VERSION 5.7 ;
  NOWIREEXTENSIONATPIN ON ;
  DIVIDERCHAR "/" ;
  BUSBITCHARS "[]" ;
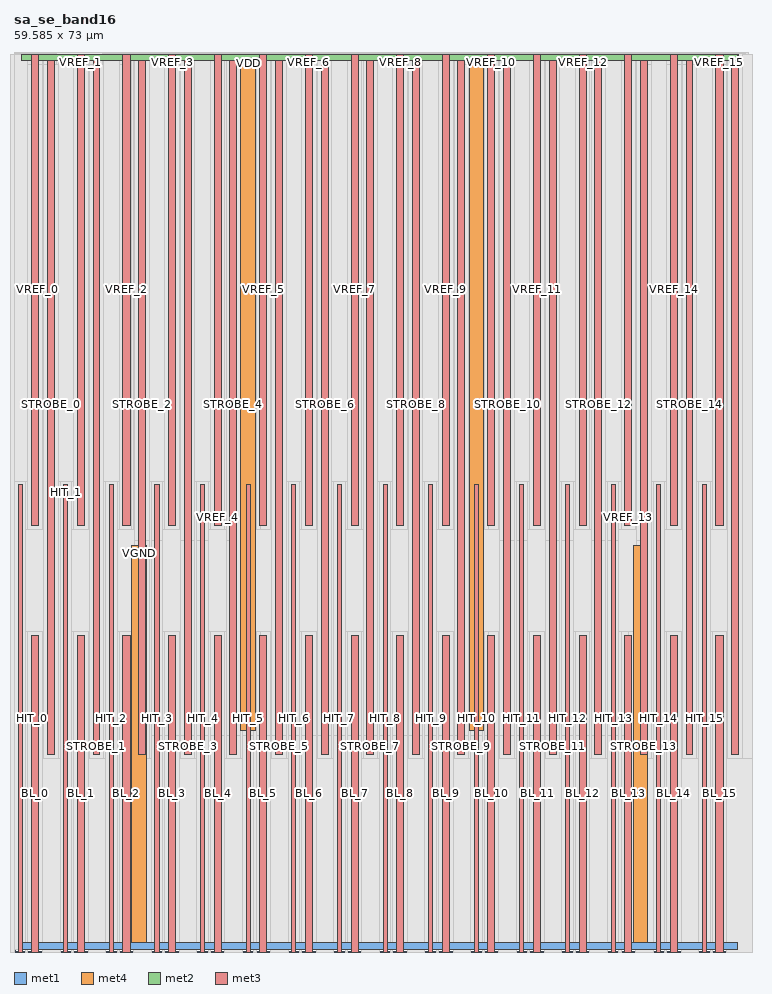
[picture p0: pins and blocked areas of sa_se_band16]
MACRO sa_se_band16
  CLASS BLOCK ;
  FOREIGN sa_se_band16 ;
  ORIGIN 0.300 0.000 ;
  SIZE 59.585 BY 73.000 ;
  PIN VGND
    USE GROUND ;
    PORT
      LAYER met1 ;
        RECT 0.300 0.200 58.360 0.800 ;
    END
    PORT
      LAYER met4 ;
        RECT 9.235 0.200 10.415 33.000 ;
    END
    PORT
      LAYER met4 ;
        RECT 49.935 0.200 51.115 33.000 ;
    END
  END VGND
  PIN VDD
    USE POWER ;
    PORT
      LAYER met2 ;
        RECT 0.300 72.300 58.360 72.800 ;
    END
    PORT
      LAYER met4 ;
        RECT 18.110 18.000 19.290 72.750 ;
    END
    PORT
      LAYER met4 ;
        RECT 36.610 18.000 37.790 72.750 ;
    END
  END VDD
  PIN HIT_0
    USE SIGNAL ;
    PORT
      LAYER met3 ;
        RECT 0.035 0.000 0.365 37.900 ;
    END
  END HIT_0
  PIN BL_0
    USE SIGNAL ;
    PORT
      LAYER met3 ;
        RECT 1.135 0.000 1.710 25.700 ;
    END
  END BL_0
  PIN VREF_0
    USE SIGNAL ;
    PORT
      LAYER met3 ;
        RECT 1.135 34.600 1.710 72.800 ;
    END
  END VREF_0
  PIN STROBE_0
    USE SIGNAL ;
    PORT
      LAYER met3 ;
        RECT 2.410 16.000 2.970 72.800 ;
    END
  END STROBE_0
  PIN HIT_1
    USE SIGNAL ;
    PORT
      LAYER met3 ;
        RECT 3.735 0.000 4.065 37.900 ;
    END
  END HIT_1
  PIN BL_1
    USE SIGNAL ;
    PORT
      LAYER met3 ;
        RECT 4.835 0.000 5.410 25.700 ;
    END
  END BL_1
  PIN VREF_1
    USE SIGNAL ;
    PORT
      LAYER met3 ;
        RECT 4.835 34.600 5.410 72.800 ;
    END
  END VREF_1
  PIN STROBE_1
    USE SIGNAL ;
    PORT
      LAYER met3 ;
        RECT 6.110 16.000 6.670 72.800 ;
    END
  END STROBE_1
  PIN HIT_2
    USE SIGNAL ;
    PORT
      LAYER met3 ;
        RECT 7.435 0.000 7.765 37.900 ;
    END
  END HIT_2
  PIN BL_2
    USE SIGNAL ;
    PORT
      LAYER met3 ;
        RECT 8.535 0.000 9.110 25.700 ;
    END
  END BL_2
  PIN VREF_2
    USE SIGNAL ;
    PORT
      LAYER met3 ;
        RECT 8.535 34.600 9.110 72.800 ;
    END
  END VREF_2
  PIN STROBE_2
    USE SIGNAL ;
    PORT
      LAYER met3 ;
        RECT 9.810 16.000 10.370 72.800 ;
    END
  END STROBE_2
  PIN HIT_3
    USE SIGNAL ;
    PORT
      LAYER met3 ;
        RECT 11.135 0.000 11.465 37.900 ;
    END
  END HIT_3
  PIN BL_3
    USE SIGNAL ;
    PORT
      LAYER met3 ;
        RECT 12.235 0.000 12.810 25.700 ;
    END
  END BL_3
  PIN VREF_3
    USE SIGNAL ;
    PORT
      LAYER met3 ;
        RECT 12.235 34.600 12.810 72.800 ;
    END
  END VREF_3
  PIN STROBE_3
    USE SIGNAL ;
    PORT
      LAYER met3 ;
        RECT 13.510 16.000 14.070 72.800 ;
    END
  END STROBE_3
  PIN HIT_4
    USE SIGNAL ;
    PORT
      LAYER met3 ;
        RECT 14.835 0.000 15.165 37.900 ;
    END
  END HIT_4
  PIN BL_4
    USE SIGNAL ;
    PORT
      LAYER met3 ;
        RECT 15.935 0.000 16.510 25.700 ;
    END
  END BL_4
  PIN VREF_4
    USE SIGNAL ;
    PORT
      LAYER met3 ;
        RECT 15.935 34.600 16.510 72.800 ;
    END
  END VREF_4
  PIN STROBE_4
    USE SIGNAL ;
    PORT
      LAYER met3 ;
        RECT 17.210 16.000 17.770 72.800 ;
    END
  END STROBE_4
  PIN HIT_5
    USE SIGNAL ;
    PORT
      LAYER met3 ;
        RECT 18.535 0.000 18.865 37.900 ;
    END
  END HIT_5
  PIN BL_5
    USE SIGNAL ;
    PORT
      LAYER met3 ;
        RECT 19.635 0.000 20.210 25.700 ;
    END
  END BL_5
  PIN VREF_5
    USE SIGNAL ;
    PORT
      LAYER met3 ;
        RECT 19.635 34.600 20.210 72.800 ;
    END
  END VREF_5
  PIN STROBE_5
    USE SIGNAL ;
    PORT
      LAYER met3 ;
        RECT 20.910 16.000 21.470 72.800 ;
    END
  END STROBE_5
  PIN HIT_6
    USE SIGNAL ;
    PORT
      LAYER met3 ;
        RECT 22.235 0.000 22.565 37.900 ;
    END
  END HIT_6
  PIN BL_6
    USE SIGNAL ;
    PORT
      LAYER met3 ;
        RECT 23.335 0.000 23.910 25.700 ;
    END
  END BL_6
  PIN VREF_6
    USE SIGNAL ;
    PORT
      LAYER met3 ;
        RECT 23.335 34.600 23.910 72.800 ;
    END
  END VREF_6
  PIN STROBE_6
    USE SIGNAL ;
    PORT
      LAYER met3 ;
        RECT 24.610 16.000 25.170 72.800 ;
    END
  END STROBE_6
  PIN HIT_7
    USE SIGNAL ;
    PORT
      LAYER met3 ;
        RECT 25.935 0.000 26.265 37.900 ;
    END
  END HIT_7
  PIN BL_7
    USE SIGNAL ;
    PORT
      LAYER met3 ;
        RECT 27.035 0.000 27.610 25.700 ;
    END
  END BL_7
  PIN VREF_7
    USE SIGNAL ;
    PORT
      LAYER met3 ;
        RECT 27.035 34.600 27.610 72.800 ;
    END
  END VREF_7
  PIN STROBE_7
    USE SIGNAL ;
    PORT
      LAYER met3 ;
        RECT 28.310 16.000 28.870 72.800 ;
    END
  END STROBE_7
  PIN HIT_8
    USE SIGNAL ;
    PORT
      LAYER met3 ;
        RECT 29.635 0.000 29.965 37.900 ;
    END
  END HIT_8
  PIN BL_8
    USE SIGNAL ;
    PORT
      LAYER met3 ;
        RECT 30.735 0.000 31.310 25.700 ;
    END
  END BL_8
  PIN VREF_8
    USE SIGNAL ;
    PORT
      LAYER met3 ;
        RECT 30.735 34.600 31.310 72.800 ;
    END
  END VREF_8
  PIN STROBE_8
    USE SIGNAL ;
    PORT
      LAYER met3 ;
        RECT 32.010 16.000 32.570 72.800 ;
    END
  END STROBE_8
  PIN HIT_9
    USE SIGNAL ;
    PORT
      LAYER met3 ;
        RECT 33.335 0.000 33.665 37.900 ;
    END
  END HIT_9
  PIN BL_9
    USE SIGNAL ;
    PORT
      LAYER met3 ;
        RECT 34.435 0.000 35.010 25.700 ;
    END
  END BL_9
  PIN VREF_9
    USE SIGNAL ;
    PORT
      LAYER met3 ;
        RECT 34.435 34.600 35.010 72.800 ;
    END
  END VREF_9
  PIN STROBE_9
    USE SIGNAL ;
    PORT
      LAYER met3 ;
        RECT 35.710 16.000 36.270 72.800 ;
    END
  END STROBE_9
  PIN HIT_10
    USE SIGNAL ;
    PORT
      LAYER met3 ;
        RECT 37.035 0.000 37.365 37.900 ;
    END
  END HIT_10
  PIN BL_10
    USE SIGNAL ;
    PORT
      LAYER met3 ;
        RECT 38.135 0.000 38.710 25.700 ;
    END
  END BL_10
  PIN VREF_10
    USE SIGNAL ;
    PORT
      LAYER met3 ;
        RECT 38.135 34.600 38.710 72.800 ;
    END
  END VREF_10
  PIN STROBE_10
    USE SIGNAL ;
    PORT
      LAYER met3 ;
        RECT 39.410 16.000 39.970 72.800 ;
    END
  END STROBE_10
  PIN HIT_11
    USE SIGNAL ;
    PORT
      LAYER met3 ;
        RECT 40.735 0.000 41.065 37.900 ;
    END
  END HIT_11
  PIN BL_11
    USE SIGNAL ;
    PORT
      LAYER met3 ;
        RECT 41.835 0.000 42.410 25.700 ;
    END
  END BL_11
  PIN VREF_11
    USE SIGNAL ;
    PORT
      LAYER met3 ;
        RECT 41.835 34.600 42.410 72.800 ;
    END
  END VREF_11
  PIN STROBE_11
    USE SIGNAL ;
    PORT
      LAYER met3 ;
        RECT 43.110 16.000 43.670 72.800 ;
    END
  END STROBE_11
  PIN HIT_12
    USE SIGNAL ;
    PORT
      LAYER met3 ;
        RECT 44.435 0.000 44.765 37.900 ;
    END
  END HIT_12
  PIN BL_12
    USE SIGNAL ;
    PORT
      LAYER met3 ;
        RECT 45.535 0.000 46.110 25.700 ;
    END
  END BL_12
  PIN VREF_12
    USE SIGNAL ;
    PORT
      LAYER met3 ;
        RECT 45.535 34.600 46.110 72.800 ;
    END
  END VREF_12
  PIN STROBE_12
    USE SIGNAL ;
    PORT
      LAYER met3 ;
        RECT 46.810 16.000 47.370 72.800 ;
    END
  END STROBE_12
  PIN HIT_13
    USE SIGNAL ;
    PORT
      LAYER met3 ;
        RECT 48.135 0.000 48.465 37.900 ;
    END
  END HIT_13
  PIN BL_13
    USE SIGNAL ;
    PORT
      LAYER met3 ;
        RECT 49.235 0.000 49.810 25.700 ;
    END
  END BL_13
  PIN VREF_13
    USE SIGNAL ;
    PORT
      LAYER met3 ;
        RECT 49.235 34.600 49.810 72.800 ;
    END
  END VREF_13
  PIN STROBE_13
    USE SIGNAL ;
    PORT
      LAYER met3 ;
        RECT 50.510 16.000 51.070 72.800 ;
    END
  END STROBE_13
  PIN HIT_14
    USE SIGNAL ;
    PORT
      LAYER met3 ;
        RECT 51.835 0.000 52.165 37.900 ;
    END
  END HIT_14
  PIN BL_14
    USE SIGNAL ;
    PORT
      LAYER met3 ;
        RECT 52.935 0.000 53.510 25.700 ;
    END
  END BL_14
  PIN VREF_14
    USE SIGNAL ;
    PORT
      LAYER met3 ;
        RECT 52.935 34.600 53.510 72.800 ;
    END
  END VREF_14
  PIN STROBE_14
    USE SIGNAL ;
    PORT
      LAYER met3 ;
        RECT 54.210 16.000 54.770 72.800 ;
    END
  END STROBE_14
  PIN HIT_15
    USE SIGNAL ;
    PORT
      LAYER met3 ;
        RECT 55.535 0.000 55.865 37.900 ;
    END
  END HIT_15
  PIN BL_15
    USE SIGNAL ;
    PORT
      LAYER met3 ;
        RECT 56.635 0.000 57.210 25.700 ;
    END
  END BL_15
  PIN VREF_15
    USE SIGNAL ;
    PORT
      LAYER met3 ;
        RECT 56.635 34.600 57.210 72.800 ;
    END
  END VREF_15
  PIN STROBE_15
    USE SIGNAL ;
    PORT
      LAYER met3 ;
        RECT 57.910 16.000 58.470 72.800 ;
    END
  END STROBE_15
  OBS
      LAYER nwell ;
        RECT -0.300 1.500 59.285 73.000 ;
      LAYER li1 ;
        RECT 0.060 5.080 59.080 72.055 ;
      LAYER met1 ;
        RECT -0.300 1.080 59.050 72.660 ;
        RECT -0.300 0.700 0.020 1.080 ;
        RECT -0.300 0.200 0.300 0.700 ;
        RECT 10.065 0.200 59.050 1.080 ;
      LAYER met2 ;
        RECT -0.300 72.800 3.120 72.915 ;
        RECT -0.300 72.630 3.400 72.800 ;
        RECT -0.300 72.370 3.285 72.630 ;
        RECT -0.300 72.300 3.400 72.370 ;
        RECT -0.300 72.020 3.120 72.300 ;
        RECT 6.880 72.020 59.060 72.915 ;
        RECT -0.300 0.185 59.060 72.020 ;
      LAYER met4 ;
        RECT 9.235 33.400 17.710 72.750 ;
        RECT 10.815 17.600 17.710 33.400 ;
        RECT 19.690 17.600 36.210 72.750 ;
        RECT 38.190 33.400 51.115 72.750 ;
        RECT 38.190 17.600 49.535 33.400 ;
        RECT 10.815 0.310 49.535 17.600 ;
        RECT 9.235 0.200 51.115 0.310 ;
      LAYER met1 ;
        RECT -0.600 0.000 -0.300 72.800 ;
      LAYER met3 ;
        RECT 2.010 0.000 3.435 15.700 ;
        RECT 5.710 0.000 7.135 15.700 ;
        RECT 9.410 0.000 10.835 15.700 ;
        RECT 13.110 0.000 14.535 15.700 ;
        RECT 16.810 0.000 18.235 15.700 ;
        RECT 20.510 0.000 21.935 15.700 ;
        RECT 24.210 0.000 25.635 15.700 ;
        RECT 27.910 0.000 29.335 15.700 ;
        RECT 31.610 0.000 33.035 15.700 ;
        RECT 35.310 0.000 36.735 15.700 ;
        RECT 39.010 0.000 40.435 15.700 ;
        RECT 42.710 0.000 44.135 15.700 ;
        RECT 46.410 0.000 47.835 15.700 ;
        RECT 50.110 0.000 51.535 15.700 ;
        RECT 53.810 0.000 55.235 15.700 ;
        RECT 57.510 0.000 59.585 15.700 ;
        RECT 0.665 0.000 0.835 26.000 ;
        RECT 2.010 15.700 2.110 26.000 ;
        RECT 4.365 0.000 4.535 26.000 ;
        RECT 5.710 15.700 5.810 26.000 ;
        RECT 8.065 0.000 8.235 26.000 ;
        RECT 9.410 15.700 9.510 26.000 ;
        RECT 11.765 0.000 11.935 26.000 ;
        RECT 13.110 15.700 13.210 26.000 ;
        RECT 15.465 0.000 15.635 26.000 ;
        RECT 16.810 15.700 16.910 26.000 ;
        RECT 19.165 0.000 19.335 26.000 ;
        RECT 20.510 15.700 20.610 26.000 ;
        RECT 22.865 0.000 23.035 26.000 ;
        RECT 24.210 15.700 24.310 26.000 ;
        RECT 26.565 0.000 26.735 26.000 ;
        RECT 27.910 15.700 28.010 26.000 ;
        RECT 30.265 0.000 30.435 26.000 ;
        RECT 31.610 15.700 31.710 26.000 ;
        RECT 33.965 0.000 34.135 26.000 ;
        RECT 35.310 15.700 35.410 26.000 ;
        RECT 37.665 0.000 37.835 26.000 ;
        RECT 39.010 15.700 39.110 26.000 ;
        RECT 41.365 0.000 41.535 26.000 ;
        RECT 42.710 15.700 42.810 26.000 ;
        RECT 45.065 0.000 45.235 26.000 ;
        RECT 46.410 15.700 46.510 26.000 ;
        RECT 48.765 0.000 48.935 26.000 ;
        RECT 50.110 15.700 50.210 26.000 ;
        RECT 52.465 0.000 52.635 26.000 ;
        RECT 53.810 15.700 53.910 26.000 ;
        RECT 56.165 0.000 56.335 26.000 ;
        RECT 57.510 15.700 57.610 26.000 ;
        RECT 0.665 26.000 2.110 34.300 ;
        RECT 4.365 26.000 5.810 34.300 ;
        RECT 8.065 26.000 9.510 34.300 ;
        RECT 11.765 26.000 13.210 34.300 ;
        RECT 15.465 26.000 16.910 34.300 ;
        RECT 19.165 26.000 20.610 34.300 ;
        RECT 22.865 26.000 24.310 34.300 ;
        RECT 26.565 26.000 28.010 34.300 ;
        RECT 30.265 26.000 31.710 34.300 ;
        RECT 33.965 26.000 35.410 34.300 ;
        RECT 37.665 26.000 39.110 34.300 ;
        RECT 41.365 26.000 42.810 34.300 ;
        RECT 45.065 26.000 46.510 34.300 ;
        RECT 48.765 26.000 50.210 34.300 ;
        RECT 52.465 26.000 53.910 34.300 ;
        RECT 56.165 26.000 57.610 34.300 ;
        RECT -0.300 0.000 -0.265 38.200 ;
        RECT 0.665 34.300 0.835 38.200 ;
        RECT 3.270 15.700 3.435 38.200 ;
        RECT 4.365 34.300 4.535 38.200 ;
        RECT 6.970 15.700 7.135 38.200 ;
        RECT 8.065 34.300 8.235 38.200 ;
        RECT 10.670 15.700 10.835 38.200 ;
        RECT 11.765 34.300 11.935 38.200 ;
        RECT 14.370 15.700 14.535 38.200 ;
        RECT 15.465 34.300 15.635 38.200 ;
        RECT 18.070 15.700 18.235 38.200 ;
        RECT 19.165 34.300 19.335 38.200 ;
        RECT 21.770 15.700 21.935 38.200 ;
        RECT 22.865 34.300 23.035 38.200 ;
        RECT 25.470 15.700 25.635 38.200 ;
        RECT 26.565 34.300 26.735 38.200 ;
        RECT 29.170 15.700 29.335 38.200 ;
        RECT 30.265 34.300 30.435 38.200 ;
        RECT 32.870 15.700 33.035 38.200 ;
        RECT 33.965 34.300 34.135 38.200 ;
        RECT 36.570 15.700 36.735 38.200 ;
        RECT 37.665 34.300 37.835 38.200 ;
        RECT 40.270 15.700 40.435 38.200 ;
        RECT 41.365 34.300 41.535 38.200 ;
        RECT 43.970 15.700 44.135 38.200 ;
        RECT 45.065 34.300 45.235 38.200 ;
        RECT 47.670 15.700 47.835 38.200 ;
        RECT 48.765 34.300 48.935 38.200 ;
        RECT 51.370 15.700 51.535 38.200 ;
        RECT 52.465 34.300 52.635 38.200 ;
        RECT 55.070 15.700 55.235 38.200 ;
        RECT 56.165 34.300 56.335 38.200 ;
        RECT -0.300 38.200 0.835 72.800 ;
        RECT 2.010 34.300 2.110 72.800 ;
        RECT 3.270 38.200 4.535 72.800 ;
        RECT 5.710 34.300 5.810 72.800 ;
        RECT 6.970 38.200 8.235 72.800 ;
        RECT 9.410 34.300 9.510 72.800 ;
        RECT 10.670 38.200 11.935 72.800 ;
        RECT 13.110 34.300 13.210 72.800 ;
        RECT 14.370 38.200 15.635 72.800 ;
        RECT 16.810 34.300 16.910 72.800 ;
        RECT 18.070 38.200 19.335 72.800 ;
        RECT 20.510 34.300 20.610 72.800 ;
        RECT 21.770 38.200 23.035 72.800 ;
        RECT 24.210 34.300 24.310 72.800 ;
        RECT 25.470 38.200 26.735 72.800 ;
        RECT 27.910 34.300 28.010 72.800 ;
        RECT 29.170 38.200 30.435 72.800 ;
        RECT 31.610 34.300 31.710 72.800 ;
        RECT 32.870 38.200 34.135 72.800 ;
        RECT 35.310 34.300 35.410 72.800 ;
        RECT 36.570 38.200 37.835 72.800 ;
        RECT 39.010 34.300 39.110 72.800 ;
        RECT 40.270 38.200 41.535 72.800 ;
        RECT 42.710 34.300 42.810 72.800 ;
        RECT 43.970 38.200 45.235 72.800 ;
        RECT 46.410 34.300 46.510 72.800 ;
        RECT 47.670 38.200 48.935 72.800 ;
        RECT 50.110 34.300 50.210 72.800 ;
        RECT 51.370 38.200 52.635 72.800 ;
        RECT 53.810 34.300 53.910 72.800 ;
        RECT 55.070 38.200 56.335 72.800 ;
        RECT 57.510 34.300 57.610 72.800 ;
        RECT 58.770 15.700 59.585 72.800 ;
  END
END sa_se_band16
END LIBRARY

